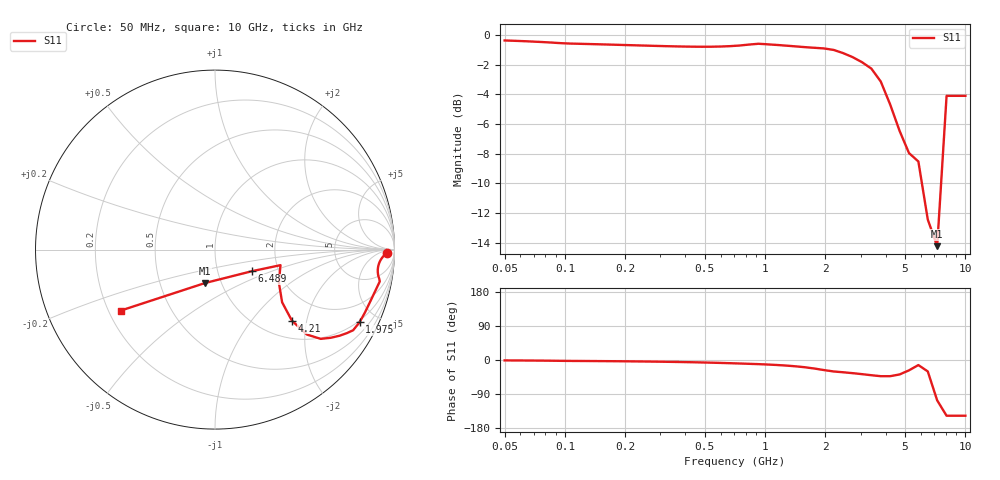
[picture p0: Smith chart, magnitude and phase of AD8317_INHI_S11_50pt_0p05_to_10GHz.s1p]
! AD8317 INHI/INLO input model, 0.05-10 GHz
! Sources: AD8317 Rev.D pp.3-4 impedance table + p.9 Figure 15 approximation
! INLO is RF common (AC-coupled to ground), modeled implicitly in single-ended S11 at INHI.
# GHZ S RI R 50
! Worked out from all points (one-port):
!   50 points, 50 MHz to 10 GHz, reference 50 ohm
!   lowest |S11| = -14.2 dB at 7.23 GHz (marker M1), VSWR 1.48, Z = 41.9 - j16.2 ohm
!   |S11| at or under -10 dB: 6.076 GHz to 7.574 GHz (1.499 GHz wide, 22 % of centre)
!   S11 on the Smith chart (normalised r, x): 50 MHz: 40, -18; 1.975 GHz: 0.93, -4.01; 4.21 GHz: 1.36, -1.64; 6.489 GHz: 1.46, -0.37; 10 GHz: 0.25, -0.28
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0.05  0.9591 -0.018
0.077056  0.9472 -0.0275
0.106583  0.9355 -0.0398
0.203914  0.9238 -0.0563
0.390127  0.9109 -0.0871
0.539617  0.9069 -0.1126
0.746388  0.9104 -0.1481
0.926583  0.918 -0.1772
1.150281  0.9016 -0.2122
1.281634  0.8906 -0.2354
1.427985  0.8768 -0.2643
1.591049  0.8591 -0.3013
1.772733  0.8355 -0.3504
1.975164  0.8052 -0.4052
2.20071  0.7696 -0.4493
2.452012  0.7343 -0.4656
2.732011  0.693 -0.48
3.043983  0.6449 -0.4913
3.39158  0.5892 -0.4973
3.778869  0.5124 -0.4735
4.210383  0.4288 -0.3961
4.691173  0.374 -0.2939
5.226864  0.3558 -0.1837
5.823727  0.3649 -0.0867
6.488747  0.2066 -0.1201
7.229706  -0.0556 -0.1863
8.055276  -0.5239 -0.3393
10  -0.5239 -0.3393
